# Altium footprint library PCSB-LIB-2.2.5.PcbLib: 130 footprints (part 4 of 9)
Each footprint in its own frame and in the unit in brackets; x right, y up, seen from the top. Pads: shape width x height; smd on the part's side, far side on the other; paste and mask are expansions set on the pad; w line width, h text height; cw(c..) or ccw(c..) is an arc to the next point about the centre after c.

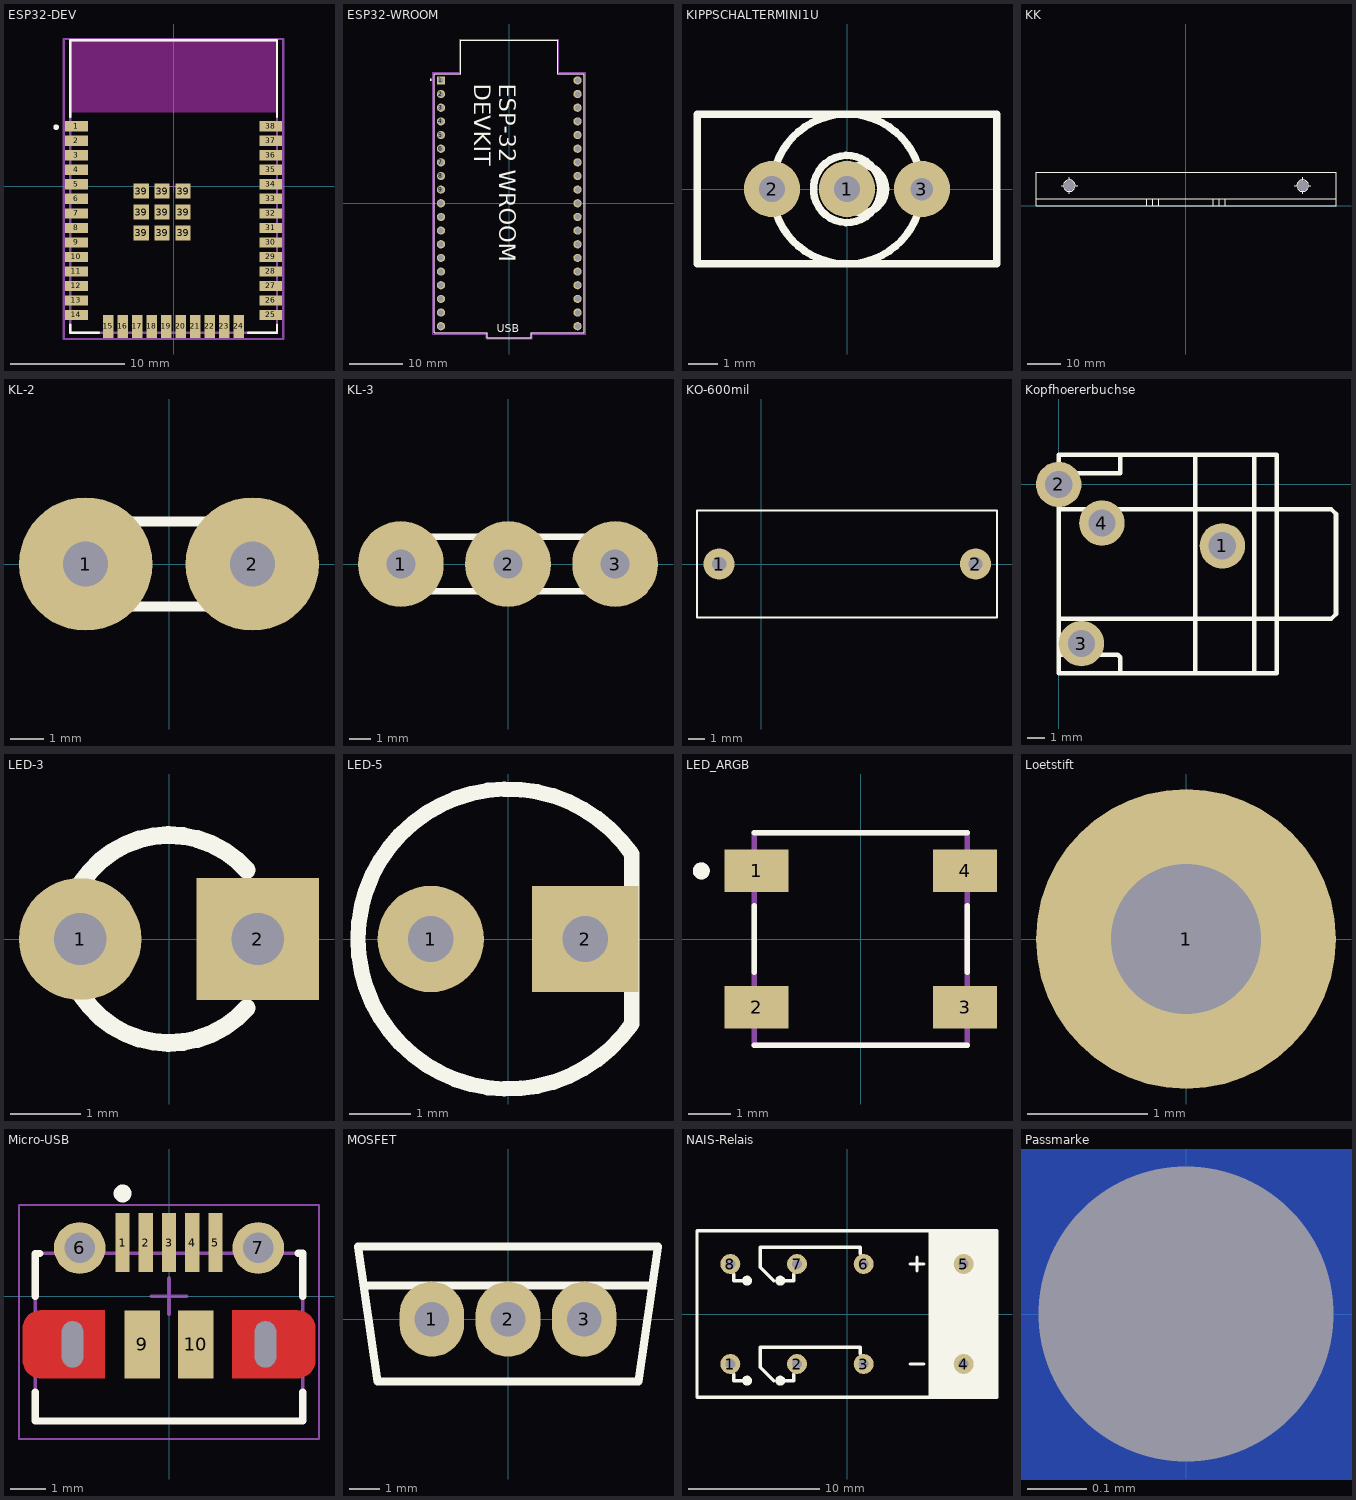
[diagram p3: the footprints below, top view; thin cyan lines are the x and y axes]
## ESP32-DEV [mm]
pads (47):
  rect 2x0.9 smd paste+0 mask+0: 1(-8.5,5.26) 2(-8.5,3.99) 3(-8.5,2.72) 4(-8.5,1.45) 5(-8.5,0.18) 6(-8.5,-1.09) 7(-8.5,-2.36) 8(-8.5,-3.63) 9(-8.5,-4.9) 10(-8.5,-6.17) 11(-8.5,-7.44) 12(-8.5,-8.71) 13(-8.5,-9.98) 14(-8.5,-11.25) 25(8.5,-11.25) 26(8.5,-9.98) 27(8.5,-8.71) 28(8.5,-7.44) 29(8.5,-6.17) 30(8.5,-4.9) 31(8.5,-3.63) 32(8.5,-2.36) 33(8.5,-1.09) 34(8.5,0.18) 35(8.5,1.45) 36(8.5,2.72) 37(8.5,3.99) 38(8.5,5.26)
  rect 0.9x2 smd paste+0 mask+0: 15(-5.715,-12.25) 16(-4.445,-12.25) 17(-3.175,-12.25) 18(-1.905,-12.25) 19(-0.635,-12.25) 20(0.635,-12.25) 21(1.905,-12.25) 22(3.175,-12.25) 23(4.445,-12.25) 24(5.715,-12.25)
  rect 1.33x1.33 smd paste+0 mask+0: 39(-2.835,-4.075) 39(-2.835,-2.24) 39(-2.835,-0.405) 39(-1,-4.075) 39(-1,-2.24) 39(-1,-0.405) 39(0.835,-4.075) 39(0.835,-2.24) 39(0.835,-0.405)
Top Overlay:
  circle w0.25: c-10.275,5.185 r0.125
  lines w0.2: -9.05,-12.075 -9.05,-12.8 -6.54,-12.8 ; -9.05,6.085 -9.05,12.8 9.05,12.8 9.05,6.085 ; 6.54,-12.8 9.05,-12.8 9.05,-12.075
Keep-Out Layer:
  rectangle: -9,6.45 9,12.75
  rectangle: -9,6.45 9,12.75
Mechanical 5:
  lines w0.2: -9.6,-13.35 -9.6,12.9 9.6,12.9 9.6,-13.35 -9.6,-13.35
Mechanical 13:
  lines w0.2: -9.05,-12.8 -9.05,12.8 9.05,12.8 9.05,-12.8 -9.05,-12.8
Mechanical 15:
  lines w0.2: -9.6,-13.35 -9.6,12.9 9.6,12.9 9.6,-13.35 -9.6,-13.35
Mechanical 16:
  lines w0.1: -0.5,0 0.5,0 ; 0,-0.5 0,0.5
3D body "UNK_Espressif_Systems_ESP32-WROOM-32D_eec.STEP": height 0.25, standoff 0, extent -9.6,-13.35 9.6,12.9

## ESP32-WROOM [mm]
pads (38):
  rect 1.53x1.53 / inner round 1.53 / far side rect 1.53x1.53 hole 1.02: 1(-12.7,22.85)
  round 1.53 hole 1.02: 2(-12.7,20.31) 3(-12.7,17.77) 4(-12.7,15.23) 5(-12.7,12.69) 6(-12.7,10.15) 7(-12.7,7.61) 8(-12.7,5.07) 9(-12.7,2.53) 10(-12.7,-0.01) 11(-12.7,-2.55) 12(-12.7,-5.09) 13(-12.7,-7.63) 14(-12.7,-10.17) 15(-12.7,-12.71) 16(-12.7,-15.25) 17(-12.7,-17.79) 18(-12.7,-20.33) 19(-12.7,-22.87) 20(12.7,-22.87) 21(12.7,-20.33) 22(12.7,-17.79) 23(12.7,-15.25) 24(12.7,-12.71) 25(12.7,-10.17) 26(12.7,-7.63) 27(12.7,-5.09) 28(12.7,-2.55) 29(12.7,-0.01) 30(12.7,2.53) 31(12.7,5.07) 32(12.7,7.61) 33(12.7,10.15) 34(12.7,12.69) 35(12.7,15.23) 36(12.7,17.77) 37(12.7,20.31) 38(12.7,22.85)
Top Overlay:
  circle w0.2: c-14.57,22.97 r0.1
  lines w0.127: -13.95,-24.1 -13.95,24.1 -9,24.1 -9,30.3 9,30.3 9,24.1 13.95,24.1 13.95,-24.1 4.06,-24.1 4.06,-25 -4.07,-25 -4.07,-24.1 -13.95,-24.1
  text "ESP-32 WROOM / DEVKIT" at -6.477,22.225 h3.05
  text "USB" at -2.286,-24.003 h1.52
Mechanical 13:
  circle w0.2: c-14.57,22.97 r0.1
  lines w0.127: -9,23.876 -9,24.1 -13.95,24.1 -13.95,-24.1 -4.07,-24.1 -4.07,-25 4.06,-25 4.06,-24.1 13.95,-24.1 13.95,24.1 9,24.1 9,23.876
Mechanical 15:
  lines w0.05: -14.2,-24.38 -14.2,24.38 -9.25,24.38 -9.25,30.55 9.25,30.55 9.25,24.38 14.2,24.38 14.2,-24.38 4.31,-24.38 4.31,-25.25 -4.32,-25.25 -4.32,-24.38 -14.2,-24.38

## KIPPSCHALTERMINI1U [mil]
pads (3):
  round 75 hole 35: 1(0,0) 2(-100,0)
  round 75 hole 30: 3(100,0)
Top Overlay:
  circle w10: c20,0 r31.62
  circle w10: c0,0 r44.72
  circle w10: c0,0 r100
  lines w10: 0,-30 cw(c0,0) 9.49,28.46 ; -200,-100 -200,100 200,100 200,-100 -200,-100

## KK [mm]
pads (2):
  rect 0x0 hole 3.2 unplated: 0(-35,6) 0(35,6)
Top Overlay:
  circle w0.254: c-35,6 r1.75
  circle w0.254: c35,6 r1.75
  lines w0.254: -45,2 45,2 ; -37.5,6 -32.5,6 ; -35,3.5 -35,8.5 ; -11.8,0 -11.8,2 ; -10,0 -10,2 ; -8.2,0 -8.2,2 ; 8.2,0 8.2,2 ; 10,0 10,2 ; 11.8,0 11.8,2 ; 32.5,6 37.5,6 ; 35,3.5 35,8.5 ; -45,0 45,0 45,10 -45,10 -45,0

## KL-2 [mm]
height 10
pads (2):
  round 4 hole 1.35: 1(-2.5,0) 2(2.5,0)
Top Overlay:
  lines w0.3: -3.81,-1.27 3.81,-1.27 3.81,1.27 -3.81,1.27 -3.81,-1.27

## KL-3 [mm]
height 10
pads (3):
  round 4 hole 1.35: 1(-5,0) 2(0,0) 3(5,0)
Top Overlay:
  lines w0.3: -5.715,-1.27 6.35,-1.27 6.35,1.27 -5.715,1.27 -5.715,-1.27

## KO-600mil [mm]
pads (2):
  round 1.85 hole 0.85: 1(-2.5,0) 2(12.7,0)
Top Overlay:
  lines w0.127: -3.81,1.27 -3.81,3.175 13.97,3.175 13.97,-3.175 -3.81,-3.175 -3.81,-1.905 -3.81,1.595

## Kopfhoererbuchse [mil]
pads (4):
  round 100 hole 60: 1(360,-135) 2(0,0) 3(50,-350) 4(95,-85)
Top Overlay:
  lines w10: 0,-375 130,-375 135,-380 135,-415 ; 0,-295 480,-295 600,-295 610,-285 610,-65 600,-55 480,-55 0,-55 ; 0,25 135,25 135,65 ; 300,-415 300,65 ; 430,-415 430,65 ; 0,-415 480,-415 480,65 0,65 0,-415

## LED-3 [mm]
pads (2):
  round 1.75 hole 0.75: 1(-1.27,0)
  rect 1.75x1.75 hole 0.75: 2(1.27,0)
Top Overlay:
  lines w0.254: 1.111,-0.988 cw(c0,0) 1.111,0.988 ; 1.397,-0.508 1.397,0.508

## LED-5 [mm]
pads (2):
  round 1.75 hole 0.75: 1(-1.27,0)
  rect 1.75x1.75 hole 0.75: 2(1.27,0)
Top Overlay:
  lines w0.254: 2.032,-1.397 cw(c0,0) 2.032,1.397 2.032,-1.397

## LED_ARGB [mm]
pads (4):
  rect 1.5x1 smd: 1(-2.45,1.6) 2(-2.45,-1.6) 3(2.45,-1.6) 4(2.45,1.6)
Top Overlay:
  circle w0.2: c-3.75,1.6 r0.1
  lines w0.127: -2.5,-2.5 2.5,-2.5 ; -2.5,-0.787 -2.5,0.787 ; -2.5,2.5 2.5,2.5 ; 2.5,-0.787 2.5,0.787
Mechanical 13:
  circle w0.2: c-3.75,1.6 r0.1
  lines w0.127: -2.5,-2.5 2.5,-2.5 2.5,2.5 -2.5,2.5 -2.5,-2.5

## Loetstift [mm]
pads (1):
  round 2.5 hole 1.25: 1(0,0)

## Micro-USB [mm] "USB, MICRO B, Body 7.491x4.695 mm, Pitch 0.65 mm"
height 2.673
pads (11):
  rect 0.4x1.65 smd: 1(-1.3,1.5) 2(-0.65,1.5) 3(0,1.5) 4(0.65,1.5) 5(1.3,1.5)
  round 1.45 hole 0.85: 6(-2.5,1.35) 7(2.5,1.35)
  rrect50% 0x0 hole 0.6 slot 1.3 at 90 deg: 8(-2.7,-1.35) 11(2.7,-1.35)
  rect 1x1.9 smd: 9(-0.75,-1.35) 10(0.75,-1.35)
Top Layer:
  circle w0.5: c3.6,-0.9 r0.25
  circle w0.5: c3.6,-1.8 r0.25
  circle w0.5: c-3.6,-0.9 r0.25
  circle w0.5: c-3.6,-1.8 r0.25
  region: 3.6,-0.9 3.6,-1.8 4.1,-1.8 4.1,-0.9
  region: 1.775,-0.4 1.775,-2.3 3.6,-2.3 3.6,-0.4
  region: -3.6,-1.8 -3.6,-0.9 -4.1,-0.9 -4.1,-1.8
  region: -1.8,-2.3 -1.8,-0.4 -3.6,-0.4 -3.6,-2.3
Top Overlay:
  circle w0.25: c-1.3,2.875 r0.125
  lines w0.2: -3.745,-2.688 -3.745,-3.5 3.745,-3.5 3.745,-2.688 ; -3.745,-0.012 -3.745,1.195 -3.614,1.195 ; 3.615,1.2 3.745,1.2 3.745,-0.012
Mechanical 13:
  lines w0.1: -3.75,1.2 3.745,1.2 3.745,-3.5 -3.745,-3.5 -3.745,1.195
Mechanical 15:
  lines w0.05: -4.2,-4 4.2,-4 4.2,2.55 -4.2,2.55 -4.2,-4
  lines w0.1: -0.5,0 0.5,0 ; 0,-0.5 0,0.5

## MOSFET [mm]
pads (3):
  oval 2.15x2.5 hole 1.15: 1(-2.54,0) 2(0,0) 3(2.54,0)
Top Overlay:
  lines w0.254: -4.812,1.125 4.808,1.125 ; -5,2.425 0,2.425 5,2.425 4.35,-2.075 0,-2.075 -4.35,-2.075 -5,2.425

## NAIS-Relais [mil]
pads (8):
  round 60 hole 30: 1(-350,-150) 2(-150,-150) 3(50,-150) 4(350,-150) 5(350,150) 6(50,150) 7(-150,150) 8(-350,150)
Top Overlay:
  circle w10: c-300,-200 r10
  circle w10: c-200,-200 r10
  circle w10: c-300,100 r10
  circle w10: c-200,100 r10
  rectangle: 250,-250 450,250
  region: -310,-190 -290,-190 -290,-210 -310,-210
  region: -210,-190 -190,-190 -190,-210 -210,-210
  region: -206,109 -192,109 -192,93 -194,91 -207,91 -207,108
  region: -306,109 -305,108 -293,108 -293,94 -295,92 -302,92 -302,103 -307,108
  region: -290,100 -300,100 -299,99 -299,90 -300,90 -302,92 -300,94 -300,102 -295,97 -295,92
  lines w10: -340,-180 -340,-200 -300,-200 ; -340,120 -340,100 -300,100 ; -220,-200 -260,-160 -260,-120 -260,-100 40,-100 40,-120 ; -220,100 -260,140 -260,180 -260,200 40,200 40,180 ; -200,-200 -160,-200 -160,-180 ; -200,100 -160,100 -160,120 ; 190,-150 230,-150 ; 190,150 230,150 ; 210,130 210,170 ; 250,-250 250,250 ; -450,-250 450,-250 450,250 -450,250 -450,-250

## Passmarke [mm]
pads (1):
  round 0 hole 0.5 unplated: 0(0,0)
Bottom Layer:
  circle w0.5: c0,0 r0.25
